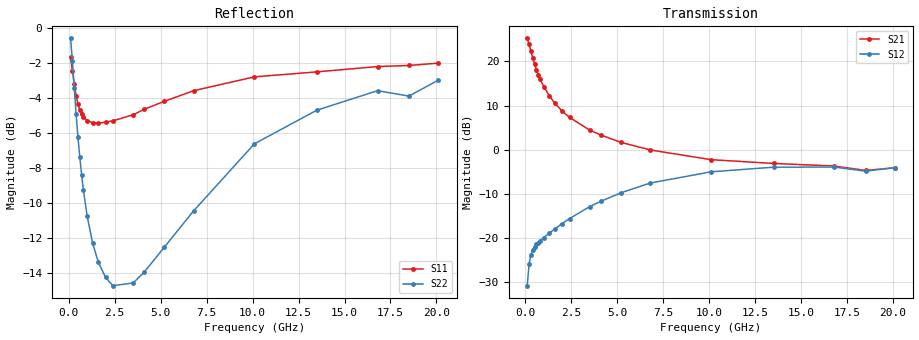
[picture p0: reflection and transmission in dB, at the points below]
!  Infineon Technologies AG
! BFR380L3 , PF131585-7, No.6, Th 09.10.01, soldered on pcb-board, measured with PP GSG850
!  Vce=2.0 V,  Ic=6.0 mA
! Common Emitter S-Parameters:  15. November 2001
#  GHz  S  MA  R  50
! f  S11  S21  S12  S22
! GHz  Mag  Ang  Mag  Ang  Mag  Ang  Mag  Ang
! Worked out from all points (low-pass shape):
!   201 points, 100 MHz to 20.1 GHz, reference 50 ohm
!   highest |S21| = 25.24 dB at 100 MHz (marker M1); lowest = -4.7 dB at 18.5 GHz (marker M2)
!   |S21| within 3 dB of the highest: start of sweep to 305.8 MHz
!   lowest |S11| = -5.5 dB at 1.6 GHz (marker M3), VSWR 3.29, Z = 15.2 - j1.45 ohm
!   |S11| at or under -10 dB: nowhere
!   |S22| runs from -14.8 to -0.6 dB; largest |S21 - S12| = 18
!   S11 on the Smith chart (normalised r, x): 100 MHz: 1.06, -2.98; 400 MHz: 0.35, -0.75; 1 GHz: 0.31, -0.21; 4.1 GHz: 0.30, +0.37; 10.1 GHz: 0.39, +1.17; 20.1 GHz: 0.96, +2.55
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0.1  0.8232 -33.5  18.28 158.3  0.02869 71.1  0.9318 -20.8
0.2  0.7536 -61.9  15.63 140.8  0.05051 60.3  0.8019 -37.6
0.3  0.6926 -84.4  13.08 127.9  0.06445 52.3  0.6726 -49.5
0.4  0.6399 -101.6  10.98 118.4  0.07311 47.4  0.5677 -58.1
0.5  0.6068 -114.9  9.339 111.2  0.07937 44.9  0.488 -64.5
0.6  0.5834 -125.8  8.077 105.6  0.08446 43.6  0.4276 -69.3
0.7  0.5674 -134.7  7.111 100.9  0.0885 43.2  0.3806 -73.2
0.8  0.5569 -142.0  6.329 96.9  0.09285 43.2  0.344 -76.6
1  0.5438 -153.5  5.184 90.4  0.1007 44.0  0.2912 -82.0
1.3  0.5363 -166.4  4.075 82.5  0.1131 45.9  0.2434 -88.7
1.6  0.5339 -176.3  3.362 76.0  0.1266 47.7  0.2155 -94.6
2  0.5384 173.3  2.738 68.4  0.1453 49.5  0.1945 -102.1
2.4  0.5425 164.6  2.321 61.6  0.1655 50.5  0.1842 -109.7
3.5  0.5648 145.1  1.665 45.3  0.2262 50.3  0.1875 -129.7
4.1  0.5855 136.4  1.466 37.8  0.2596 48.8  0.2011 -141.9
5.2  0.6168 122.4  1.21 25.4  0.3244 43.6  0.2371 -160.3
6.8  0.6614 104.2  0.992 11.0  0.4187 34.7  0.3011 172.9
10.1  0.724 77.6  0.7702 -8.2  0.5611 12.8  0.4669 132.7
13.5  0.7481 59.5  0.6977 -22.4  0.6328 -9.1  0.5821 101.0
16.8  0.7746 47.6  0.6523 -33.5  0.635 -25.6  0.6613 78.1
18.5  0.7801 45.6  0.5817 -40.6  0.5706 -34.1  0.6382 72.2
20.1  0.7921 38.5  0.625 -44.3  0.6243 -39.3  0.7083 61.3
